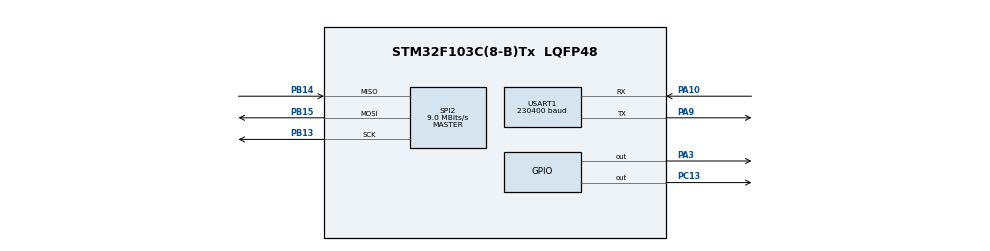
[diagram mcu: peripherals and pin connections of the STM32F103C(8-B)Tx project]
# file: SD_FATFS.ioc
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FATFS._MAX_SS=4096
FATFS._USE_LFN=1
Mcu.Family=STM32F1
Mcu.Name=STM32F103C(8-B)Tx
Mcu.Package=LQFP48
NVIC.PriorityGroup=NVIC_PRIORITYGROUP_4
NVIC.TIM2_IRQn=true\:0\:0\:false\:false\:true
NVIC.USART1_IRQn=true\:0\:0\:false\:false\:true
PA10.Mode=Asynchronous
PA10.Signal=USART1_RX
PA13.Mode=Serial_Wire
PA13.Signal=SYS_JTMS-SWDIO
PA14.Mode=Serial_Wire
PA14.Signal=SYS_JTCK-SWCLK
PA3.GPIO_Speed=GPIO_SPEED_FREQ_MEDIUM
PA3.Signal=GPIO_Output
PA9.Mode=Asynchronous
PA9.Signal=USART1_TX
PB13.Mode=Full_Duplex_Master
PB13.Signal=SPI2_SCK
PB14.Mode=Full_Duplex_Master
PB14.Signal=SPI2_MISO
PB15.Mode=Full_Duplex_Master
PB15.Signal=SPI2_MOSI
PC13-TAMPER-RTC.GPIO_Speed=GPIO_SPEED_FREQ_MEDIUM
PC13-TAMPER-RTC.Signal=GPIO_Output
PD0-OSC_IN.Mode=HSE-External-Oscillator
PD0-OSC_IN.Signal=RCC_OSC_IN
PD1-OSC_OUT.Mode=HSE-External-Oscillator
PD1-OSC_OUT.Signal=RCC_OSC_OUT
ProjectManager.HeapSize=0x200
ProjectManager.StackSize=0x400
ProjectManager.TargetToolchain=Makefile
RCC.AHBFreq_Value=72000000
RCC.APB1CLKDivider=RCC_HCLK_DIV2
RCC.APB1Freq_Value=36000000
RCC.APB1TimFreq_Value=72000000
RCC.APB2Freq_Value=72000000
RCC.APB2TimFreq_Value=72000000
RCC.HCLKFreq_Value=72000000
RCC.PLLMUL=RCC_PLL_MUL9
RCC.PLLSourceVirtual=RCC_PLLSOURCE_HSE
RCC.SYSCLKFreq_VALUE=72000000
RCC.SYSCLKSource=RCC_SYSCLKSOURCE_PLLCLK
RCC.USBFreq_Value=72000000
SPI2.BaudRatePrescaler=SPI_BAUDRATEPRESCALER_4
SPI2.CalculateBaudRate=9.0 MBits/s
SPI2.Direction=SPI_DIRECTION_2LINES
SPI2.Mode=SPI_MODE_MASTER
SPI2.VirtualType=VM_MASTER
TIM2.Period=10
TIM2.Prescaler=39999
USART1.BaudRate=230400
USART1.VirtualMode=VM_ASYNC
VP_FATFS_VS_Generic.Mode=User_defined
VP_TIM2_VS_ClockSourceINT.Mode=Internal
board=SD_FATFS

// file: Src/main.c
/**
  ******************************************************************************
  * File Name          : main.c
  * Description        : Main program body
  ******************************************************************************
  * This notice applies to any and all portions of this file
  * that are not between comment pairs USER CODE BEGIN and
  * USER CODE END. Other portions of this file, whether
  * inserted by the user or by software development tools
  * are owned by their respective copyright owners.
  *
  * Copyright (c) 2017 STMicroelectronics International N.V.
  * All rights reserved.
  *
  * Redistribution and use in source and binary forms, with or without
  * modification, are permitted, provided that the following conditions are met:
  *
  * 1. Redistribution of source code must retain the above copyright notice,
  *    this list of conditions and the following disclaimer.
  * 2. Redistributions in binary form must reproduce the above copyright notice,
  *    this list of conditions and the following disclaimer in the documentation
  *    and/or other materials provided with the distribution.
  * 3. Neither the name of STMicroelectronics nor the names of other
  *    contributors to this software may be used to endorse or promote products
  *    derived from this software without specific written permission.
  * 4. This software, including modifications and/or derivative works of this
  *    software, must execute solely and exclusively on microcontroller or
  *    microprocessor devices manufactured by or for STMicroelectronics.
  * 5. Redistribution and use of this software other than as permitted under
  *    this license is void and will automatically terminate your rights under
  *    this license.
  *
  * THIS SOFTWARE IS PROVIDED BY STMICROELECTRONICS AND CONTRIBUTORS "AS IS"
  * AND ANY EXPRESS, IMPLIED OR STATUTORY WARRANTIES, INCLUDING, BUT NOT
  * LIMITED TO, THE IMPLIED WARRANTIES OF MERCHANTABILITY, FITNESS FOR A
  * PARTICULAR PURPOSE AND NON-INFRINGEMENT OF THIRD PARTY INTELLECTUAL PROPERTY
  * RIGHTS ARE DISCLAIMED TO THE FULLEST EXTENT PERMITTED BY LAW. IN NO EVENT
  * SHALL STMICROELECTRONICS OR CONTRIBUTORS BE LIABLE FOR ANY DIRECT, INDIRECT,
  * INCIDENTAL, SPECIAL, EXEMPLARY, OR CONSEQUENTIAL DAMAGES (INCLUDING, BUT NOT
  * LIMITED TO, PROCUREMENT OF SUBSTITUTE GOODS OR SERVICES; LOSS OF USE, DATA,
  * OR PROFITS; OR BUSINESS INTERRUPTION) HOWEVER CAUSED AND ON ANY THEORY OF
  * LIABILITY, WHETHER IN CONTRACT, STRICT LIABILITY, OR TORT (INCLUDING
  * NEGLIGENCE OR OTHERWISE) ARISING IN ANY WAY OUT OF THE USE OF THIS SOFTWARE,
  * EVEN IF ADVISED OF THE POSSIBILITY OF SUCH DAMAGE.
  *
  ******************************************************************************
  */
#include "main.h"
#include "stm32f1xx_hal.h"
#include "fatfs.h"

/* USER CODE BEGIN Includes */
#include "sd.h"
/* USER CODE END Includes */

SPI_HandleTypeDef hspi2;

TIM_HandleTypeDef htim2;

UART_HandleTypeDef huart1;

/* USER CODE BEGIN PV */
/* Private variables ---------------------------------------------------------*/
volatile uint16_t Timer1=0;
uint8_t sect[512];
// char buffer1[512] ="Selection of VAM is set by the previous address set instruction. If the address set instruction of RAM is not performed before this instruction, the data that has been read first is invalid, as the direction of AC is not yet determined. If RAM data is read several times without RAM address instructions set before, read operation, the correct RAM data can be obtained from the second. But the first data would be incorrect, as there is no time margin to transfer RAM data. In case of DDRAM read operation The..."; // Буфер данных для записи/чтения
extern char str1[60];
uint32_t byteswritten,bytesread;
uint8_t result;
extern char USER_Path[4]; /* logical drive path */
FATFS SDFatFs;
FATFS *fs;
FIL MyFile;
/* USER CODE END PV */

void SystemClock_Config(void);
static void MX_GPIO_Init(void);
static void MX_SPI2_Init(void);
static void MX_TIM2_Init(void);
static void MX_USART1_UART_Init(void);

/* USER CODE BEGIN PFP */
/* Private function prototypes -----------------------------------------------*/

/* USER CODE END PFP */

/* USER CODE BEGIN 0 */
FRESULT ReadLongFile(void)
{
  uint16_t i=0, i1=0;
  uint32_t ind=0;
  uint32_t f_size = MyFile.fsize;
  sprintf(str1,"fsize: %lu\r\n",(unsigned long)f_size);
  HAL_UART_Transmit(&huart1,(uint8_t*)str1,strlen(str1),0x1000);
  ind=0;
  do
  {
    if(f_size<512)
    {
      i1=f_size;
    }
    else
    {
      i1=512;
    }
    f_size-=i1;
    f_lseek(&MyFile,ind);
    f_read(&MyFile,sect,i1,(UINT *)&bytesread);
    for(i=0;i<bytesread;i++)
    {
      HAL_UART_Transmit(&huart1,sect+i,1,0x1000);
    }
    ind+=i1;
  }
  while(f_size>0);
  HAL_UART_Transmit(&huart1,(uint8_t*)"\r\n",2,0x1000);
  return FR_OK;
}

/* USER CODE END 0 */

int main(void)
{

  /* USER CODE BEGIN 1 */
  uint16_t i;
  FRESULT res; // результат выполнения
  uint8_t wtext[]="Hello from STM32!!!";
  FILINFO fileInfo;
  char *fn;
  DIR dir;
  DWORD fre_clust, fre_sect, tot_sect;
  /* USER CODE END 1 */

  /* MCU Configuration----------------------------------------------------------*/

  /* Reset of all peripherals, Initializes the Flash interface and the Systick. */
  HAL_Init();

  /* Configure the system clock */
  SystemClock_Config();

  /* Initialize all configured peripherals */
  MX_GPIO_Init();
  MX_SPI2_Init();
  MX_TIM2_Init();
  MX_USART1_UART_Init();
  MX_FATFS_Init();

  /* USER CODE BEGIN 2 */
  HAL_TIM_Base_Start_IT(&htim2);
  // SD_PowerOn();
  // sd_ini();
  // SD_Write_Block((uint8_t*)buffer1,0x0400); // Запишем блок в буфер
  // SD_Read_Block(sect,0x0400); // Считаем блок из буфера
  // for(i=0;i<512;i++) HAL_UART_Transmit(&huart1,sect+i,1,0x1000);
  // HAL_UART_Transmit(&huart1,(uint8_t*)"\r\n",2,0x1000);
  disk_initialize(SDFatFs.drv);

  // read
  /*
  if(f_mount(&SDFatFs,(TCHAR const*)USER_Path,0)!=FR_OK)
  {
    Error_Handler();
  }
  else
  {
    if(f_open(&MyFile,"123.txt",FA_READ)!=FR_OK)
    {
      Error_Handler();
    }
    else
    {
      ReadLongFile();
      f_close(&MyFile);
    }
  }
  */

  // write
  /*
  if(f_mount(&SDFatFs,(TCHAR const*)USER_Path,0)!=FR_OK)
  {
    Error_Handler();
  }
  else
  {
    if(f_open(&MyFile,"mywrite.txt",FA_CREATE_ALWAYS|FA_WRITE)!=FR_OK)
    {
      Error_Handler();
    }
    else
    {
      res=f_write(&MyFile,wtext,sizeof(wtext),(void*)&byteswritten);
      if((byteswritten==0)||(res!=FR_OK))
      {
        Error_Handler();
      }
      f_close(&MyFile);
    }
  }
  */

  // read dir
  if(f_mount(&SDFatFs,(TCHAR const*)USER_Path,0)!=FR_OK)
  {
    Error_Handler();
  }
  else
  {
    fileInfo.lfname = (char*)sect;
    fileInfo.lfsize = sizeof(sect);
    result = f_opendir(&dir, "/");
    if (result == FR_OK)
    {
      while(1)
      {
        result = f_readdir(&dir, &fileInfo);
        if (result==FR_OK && fileInfo.fname[0])
        {
          fn = fileInfo.lfname;
          if(strlen(fn)) HAL_UART_Transmit(&huart1,(uint8_t*)fn,strlen(fn),0x1000);
          else HAL_UART_Transmit(&huart1,(uint8_t*)fileInfo.fname,strlen((char*)fileInfo.fname),0x1000);
          if(fileInfo.fattrib&AM_DIR)
          {
            HAL_UART_Transmit(&huart1,(uint8_t*)" [DIR]",7,0x1000);
          }
        }
        else break;
        HAL_UART_Transmit(&huart1,(uint8_t*)"\r\n",2,0x1000);
      }
      f_closedir(&dir);
    }
  }
  f_getfree("/", &fre_clust, &fs);
  sprintf(str1,"fre_clust: %lu\r\n",fre_clust);
  HAL_UART_Transmit(&huart1,(uint8_t*)str1,strlen(str1),0x1000);
  sprintf(str1,"n_fatent: %lu\r\n",fs->n_fatent);
  HAL_UART_Transmit(&huart1,(uint8_t*)str1,strlen(str1),0x1000);
  sprintf(str1,"fs_csize: %d\r\n",fs->csize);
  HAL_UART_Transmit(&huart1,(uint8_t*)str1,strlen(str1),0x1000);
  tot_sect = (fs->n_fatent - 2) * fs->csize;
  sprintf(str1,"tot_sect: %lu\r\n",tot_sect);
  HAL_UART_Transmit(&huart1,(uint8_t*)str1,strlen(str1),0x1000);
  fre_sect = fre_clust * fs->csize;
  sprintf(str1,"fre_sect: %lu\r\n",fre_sect);
  HAL_UART_Transmit(&huart1,(uint8_t*)str1,strlen(str1),0x1000);
  sprintf(str1, "%lu KB total drive space.\r\n%lu KB available.\r\n",
  fre_sect/2, tot_sect/2);
  HAL_UART_Transmit(&huart1,(uint8_t*)str1,strlen(str1),0x1000);
  FATFS_UnLinkDriver(USER_Path);
  /* USER CODE END 2 */

  /* Infinite loop */
  while (1)
  {

  }

}

/** System Clock Configuration
*/
void SystemClock_Config(void)
{

  RCC_OscInitTypeDef RCC_OscInitStruct;
  RCC_ClkInitTypeDef RCC_ClkInitStruct;

    /**Initializes the CPU, AHB and APB busses clocks
    */
  RCC_OscInitStruct.OscillatorType = RCC_OSCILLATORTYPE_HSE;
  RCC_OscInitStruct.HSEState = RCC_HSE_ON;
  RCC_OscInitStruct.HSEPredivValue = RCC_HSE_PREDIV_DIV1;
  RCC_OscInitStruct.HSIState = RCC_HSI_ON;
  RCC_OscInitStruct.PLL.PLLState = RCC_PLL_ON;
  RCC_OscInitStruct.PLL.PLLSource = RCC_PLLSOURCE_HSE;
  RCC_OscInitStruct.PLL.PLLMUL = RCC_PLL_MUL5;
  if (HAL_RCC_OscConfig(&RCC_OscInitStruct) != HAL_OK)
  {
    _Error_Handler(__FILE__, __LINE__);
  }

    /**Initializes the CPU, AHB and APB busses clocks
    */
  RCC_ClkInitStruct.ClockType = RCC_CLOCKTYPE_HCLK|RCC_CLOCKTYPE_SYSCLK
                              |RCC_CLOCKTYPE_PCLK1|RCC_CLOCKTYPE_PCLK2;
  RCC_ClkInitStruct.SYSCLKSource = RCC_SYSCLKSOURCE_PLLCLK;
  RCC_ClkInitStruct.AHBCLKDivider = RCC_SYSCLK_DIV1;
  RCC_ClkInitStruct.APB1CLKDivider = RCC_HCLK_DIV2;
  RCC_ClkInitStruct.APB2CLKDivider = RCC_HCLK_DIV1;

  if (HAL_RCC_ClockConfig(&RCC_ClkInitStruct, FLASH_LATENCY_1) != HAL_OK)
  {
    _Error_Handler(__FILE__, __LINE__);
  }

    /**Configure the Systick interrupt time
    */
  HAL_SYSTICK_Config(HAL_RCC_GetHCLKFreq()/1000);

    /**Configure the Systick
    */
  HAL_SYSTICK_CLKSourceConfig(SYSTICK_CLKSOURCE_HCLK);

  /* SysTick_IRQn interrupt configuration */
  HAL_NVIC_SetPriority(SysTick_IRQn, 0, 0);
}

/* SPI2 init function */
static void MX_SPI2_Init(void)
{

  hspi2.Instance = SPI2;
  hspi2.Init.Mode = SPI_MODE_MASTER;
  hspi2.Init.Direction = SPI_DIRECTION_2LINES;
  hspi2.Init.DataSize = SPI_DATASIZE_8BIT;
  hspi2.Init.CLKPolarity = SPI_POLARITY_LOW;
  hspi2.Init.CLKPhase = SPI_PHASE_1EDGE;
  hspi2.Init.NSS = SPI_NSS_SOFT;
  hspi2.Init.BaudRatePrescaler = SPI_BAUDRATEPRESCALER_4;
  hspi2.Init.FirstBit = SPI_FIRSTBIT_MSB;
  hspi2.Init.TIMode = SPI_TIMODE_DISABLE;
  hspi2.Init.CRCCalculation = SPI_CRCCALCULATION_DISABLE;
  hspi2.Init.CRCPolynomial = 10;
  if (HAL_SPI_Init(&hspi2) != HAL_OK)
  {
    _Error_Handler(__FILE__, __LINE__);
  }

}

/* TIM2 init function */
static void MX_TIM2_Init(void)
{

  TIM_ClockConfigTypeDef sClockSourceConfig;
  TIM_MasterConfigTypeDef sMasterConfig;

  htim2.Instance = TIM2;
  htim2.Init.Prescaler = 39999;
  htim2.Init.CounterMode = TIM_COUNTERMODE_UP;
  htim2.Init.Period = 10;
  htim2.Init.ClockDivision = TIM_CLOCKDIVISION_DIV1;
  htim2.Init.AutoReloadPreload = TIM_AUTORELOAD_PRELOAD_DISABLE;
  if (HAL_TIM_Base_Init(&htim2) != HAL_OK)
  {
    _Error_Handler(__FILE__, __LINE__);
  }

  sClockSourceConfig.ClockSource = TIM_CLOCKSOURCE_INTERNAL;
  if (HAL_TIM_ConfigClockSource(&htim2, &sClockSourceConfig) != HAL_OK)
  {
    _Error_Handler(__FILE__, __LINE__);
  }

  sMasterConfig.MasterOutputTrigger = TIM_TRGO_RESET;
  sMasterConfig.MasterSlaveMode = TIM_MASTERSLAVEMODE_DISABLE;
  if (HAL_TIMEx_MasterConfigSynchronization(&htim2, &sMasterConfig) != HAL_OK)
  {
    _Error_Handler(__FILE__, __LINE__);
  }

}

/* USART1 init function */
static void MX_USART1_UART_Init(void)
{

  huart1.Instance = USART1;
  huart1.Init.BaudRate = 230400;
  huart1.Init.WordLength = UART_WORDLENGTH_8B;
  huart1.Init.StopBits = UART_STOPBITS_1;
  huart1.Init.Parity = UART_PARITY_NONE;
  huart1.Init.Mode = UART_MODE_TX_RX;
  huart1.Init.HwFlowCtl = UART_HWCONTROL_NONE;
  huart1.Init.OverSampling = UART_OVERSAMPLING_16;
  if (HAL_UART_Init(&huart1) != HAL_OK)
  {
    _Error_Handler(__FILE__, __LINE__);
  }

}

/** Configure pins as
        * Analog
        * Input
        * Output
        * EVENT_OUT
        * EXTI
*/
static void MX_GPIO_Init(void)
{

  GPIO_InitTypeDef GPIO_InitStruct;

  /* GPIO Ports Clock Enable */
  __HAL_RCC_GPIOC_CLK_ENABLE();
  __HAL_RCC_GPIOD_CLK_ENABLE();
  __HAL_RCC_GPIOA_CLK_ENABLE();
  __HAL_RCC_GPIOB_CLK_ENABLE();

  /*Configure GPIO pin Output Level */
  HAL_GPIO_WritePin(GPIOC, GPIO_PIN_13, GPIO_PIN_RESET);

  /*Configure GPIO pin Output Level */
  HAL_GPIO_WritePin(GPIOA, GPIO_PIN_3, GPIO_PIN_RESET);

  /*Configure GPIO pin : PC13 */
  GPIO_InitStruct.Pin = GPIO_PIN_13;
  GPIO_InitStruct.Mode = GPIO_MODE_OUTPUT_PP;
  GPIO_InitStruct.Speed = GPIO_SPEED_FREQ_MEDIUM;
  HAL_GPIO_Init(GPIOC, &GPIO_InitStruct);

  /*Configure GPIO pin : PA3 */
  GPIO_InitStruct.Pin = GPIO_PIN_3;
  GPIO_InitStruct.Mode = GPIO_MODE_OUTPUT_PP;
  GPIO_InitStruct.Speed = GPIO_SPEED_FREQ_MEDIUM;
  HAL_GPIO_Init(GPIOA, &GPIO_InitStruct);

}

/* USER CODE BEGIN 4 */
// ----------------------------------------------------------
void HAL_TIM_PeriodElapsedCallback(TIM_HandleTypeDef *htim)
{
  if(htim==&htim2)
  {
    Timer1++;
  }
}

// ----------------------------------------------------------
/* USER CODE END 4 */

void _Error_Handler(char * file, int line)
{
  while(1)
  {
  }
}

/************************ (C) COPYRIGHT STMicroelectronics *****END OF FILE****/
